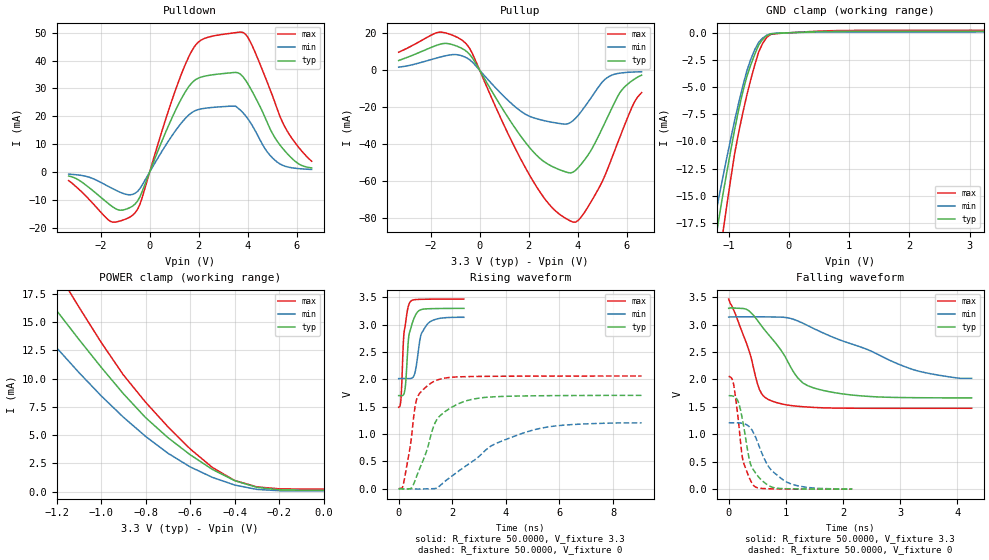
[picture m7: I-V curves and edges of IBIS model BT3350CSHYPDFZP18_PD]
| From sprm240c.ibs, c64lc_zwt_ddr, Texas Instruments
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|   Model Cell BT3350CSHYPDFZP18
[Model]   BT3350CSHYPDFZP18_PD
Model_type   I/O
Polarity   Non-Inverting
Enable   Active-Low
Vinl =  0.8V
Vinh =  2V
Cref =  15.0000pF
Rref =  100.0000M
Vref =  0V
Vmeas =  1.65
C_comp   1.700009p   1.65486p   1.747447p
[Model Spec]
Vinl   0.8V   0.8V   0.8V
Vinh   2V   2V   2V
[Temperature Range]   25   125   -40
[Voltage Range]   3.3   3.14   3.47
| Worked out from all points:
|   slope of the pulldown table from 0 to 0.495 V, typ, clamps not added: 45.1 ohm
|   slope of the pullup table from 0 to 0.495 V, typ, clamps not added: 43.8 ohm
|   GND clamp passes 1 mA (typ) near -0.48 V on its own axis
|   POWER clamp passes 1 mA (typ) near -0.40 V on its own axis
|   rising waveform, R_fixture 50.0000, V_fixture 3.3: 20-80 % time 205ps typ, 283ps min, 156ps max; typ from 1.7 V to 3.29 V
|   rising waveform, R_fixture 50.0000, V_fixture 0: 20-80 % time 856ps typ, 2.32ns min, 382ps max; typ from 0 V to 1.71 V
|   falling waveform, R_fixture 50.0000, V_fixture 3.3: 20-80 % time 667ps typ, 1.54ns min, 357ps max; typ from 3.3 V to 1.66 V
|   falling waveform, R_fixture 50.0000, V_fixture 0: 20-80 % time 215ps typ, 397ps min, 162ps max; typ from 1.7 V to 0.002 V
[POWER_clamp]
|   voltage   I(typ)   I(min)   I(max)
-3.3V     82.99mA    62.31mA    100.8mA
-1.4V     21.51mA    17.33mA    26.18mA
-1.267V   17.8mA     14.25mA    21.77mA
-1.233V   16.92mA    13.5mA     20.67mA
-1.133V   14.33mA    11.28mA    17.43mA
-900mV    8.67mA     6.594mA    10.34mA
-800mV    6.551mA    4.892mA    7.912mA
-600mV    3.27mA     2.197mA    3.79mA
-500mV    1.971mA    1.27mA     2.143mA
-400mV    978.7uA    590.6uA    989.7uA
-300mV    386.3uA    203.8uA    426.6uA
0V        134.3uA    72.54uA    231uA
[Pulldown]
|   voltage   I(typ)   I(min)   I(max)
-3.3V     -1.415mA   -746uA     -3.052mA
-1.6V     -11.86mA   -5.526mA   -17.66mA
-700mV    -12.23mA   -8.018mA   -15.5mA
-400mV    -8.952mA   -5.978mA   -11.65mA
900mV     19.24mA    12.9mA     25.53mA
1.7V      31.81mA    21.22mA    43.17mA
2.2V      34.3mA     22.8mA     47.78mA
3.7V      35.12mA    22.19mA    50.19mA
4.1V      30.16mA    17.85mA    46.75mA
5.1V      12.38mA    4.293mA    25.08mA
5.7V      5.755mA    1.687mA    13.38mA
6.6V      1.491mA    937.8uA    3.885mA
[Pullup]
|   voltage   I(typ)   I(min)   I(max)
-3.3V     5.278mA    1.679mA    9.743mA
-1.7V     13.72mA    6.799mA    20.48mA
-600mV    10.83mA    7.151mA    14.99mA
1.3V      -28.42mA   -18.04mA   -38.22mA
2.2V      -44.3mA    -25.71mA   -60.41mA
3V        -52.29mA   -28.23mA   -74.9mA
3.8V      -55.14mA   -27.3mA    -82.1mA
4.3V      -48.01mA   -19.44mA   -76.31mA
5.2V      -25.74mA   -3.982mA   -53.85mA
5.8V      -10.57mA   -1.415mA   -33.25mA
6.3V      -4.872mA   -941uA     -17.38mA
6.6V      -2.663mA   -794.7uA   -12.11mA
[GND_clamp]
|   voltage   I(typ)   I(min)   I(max)
-3.3V     -102mA     -77.67mA   -122mA
-1.3V     -22.07mA   -19.16mA   -26.6mA
-1.233V   -19.65mA   -17.23mA   -23.92mA
-1.167V   -17.32mA   -15.33mA   -21.26mA
-1.1V     -15.08mA   -13.44mA   -18.61mA
-1.033V   -12.97mA   -11.61mA   -16.04mA
-900mV    -8.917mA   -8.084mA   -11.14mA
-700mV    -4.089mA   -3.566mA   -5.808mA
-500mV    -1.121mA   -869uA     -1.76mA
-366.7mV  -263.4uA   -227.2uA   -428.1uA
633.3mV   109.6uA    61.6uA     173.5uA
3.233V    134.1uA    74.92uA    229.9uA
[Ramp]
| variable   typ   min   max
dV/dt_f  0.9847599/0.6632085n  0.7323867/1.723531n   1.200201/0.358252n
dV/dt_r   1.029494/0.8598868n  0.7430672/2.445214n   1.240708/0.3818052n
R_load = 50
[Rising Waveform]
R_fixture = 50.0000
V_fixture = 3.3
V_fixture_min = 3.14
V_fixture_max = 3.47
|   time   V(typ)   V(min)   V(max)
0s        1.701V     2.012V     1.489V
88ps      1.702V     2.013V     1.658V
176ps     1.715V     2.013V     2.685V
232ps     1.805V     2.013V     2.943V
360ps     2.7V       2.013V     3.334V
416ps     2.873V     2.013V     3.404V
584ps     3.126V     2.081V     3.453V
816ps     3.268V     2.781V     3.459V
1.056ns   3.287V     2.998V     3.462V
2.432ns   3.294V     3.132V     3.465V
[Rising Waveform]
R_fixture = 50.0000
V_fixture = 0
V_fixture_min = 0
V_fixture_max = 0
|   time   V(typ)   V(min)   V(max)
0s        45.61uV    24.35uV    73.91uV
200ps     -6.345mV   30.5uV     139.3mV
472ps     11.97mV    -1.303mV   917.6mV
584ps     117.3mV    -2.375mV   1.407V
672ps     231.3mV    -4.815mV   1.635V
1.36ns    1.206V     4.286mV    1.971V
2.552ns   1.61V      432.2mV    2.048V
3.504ns   1.679V     797.9mV    2.054V
4.72ns    1.696V     1.029V     2.057V
9.064ns   1.706V     1.203V     2.059V
[Falling Waveform]
R_fixture = 50.0000
V_fixture = 3.3
V_fixture_min = 3.14
V_fixture_max = 3.47
|   time   V(typ)   V(min)   V(max)
0s        3.297V     3.138V     3.465V
352ps     3.252V     3.142V     2.539V
536ps     3.031V     3.143V     1.822V
712ps     2.799V     3.14V      1.626V
920ps     2.526V     3.136V     1.557V
1.2ns     2.039V     3.07V      1.512V
1.48ns    1.848V     2.932V     1.491V
2.224ns   1.709V     2.622V     1.476V
3.208ns   1.669V     2.186V     1.475V
4.248ns   1.664V     2.02V      1.475V
[Falling Waveform]
R_fixture = 50.0000
V_fixture = 0
V_fixture_min = 0
V_fixture_max = 0
|   time   V(typ)   V(min)   V(max)
0s        1.704V     1.209V     2.057V
88ps      1.693V     1.21V      1.902V
168ps     1.591V     1.21V      1.268V
248ps     1.231V     1.199V     533mV
368ps     512.3mV    1.131V     192.2mV
456ps     317.2mV    982.1mV    48.57mV
704ps     63.91mV    402.9mV    8.245mV
1.016ns   8.732mV    129.5mV    3.629mV
1.448ns   4.013mV    25.25mV    1.725mV
2.16ns    2.321mV    6.408mV    863.5uV
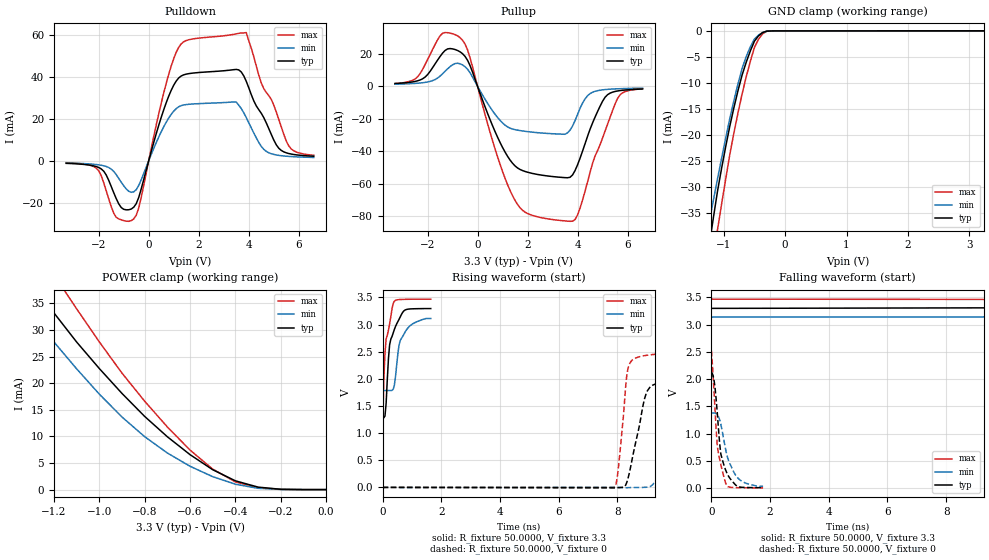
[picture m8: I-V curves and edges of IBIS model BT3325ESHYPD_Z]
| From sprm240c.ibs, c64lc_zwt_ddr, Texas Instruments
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|   Model Cell BT3325ESHYPDFZSCP18
[Model]   BT3325ESHYPD_Z
Model_type   I/O
Polarity   Non-Inverting
Enable   Active-Low
Vinl =  0.8V
Vinh =  2V
Cref =  15.0000pF
Rref =  100.0000M
Vref =  0V
Vmeas =  1.65
C_comp   2.519588p   2.450856p   2.584209p
[Model Spec]
Vinl   0.8V   0.8V   0.8V
Vinh   2V   2V   2V
[Temperature Range]   25   125   -40
[Voltage Range]   3.3   3.14   3.47
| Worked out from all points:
|   slope of the pulldown table from 0 to 0.495 V, typ, clamps not added: 24.1 ohm
|   slope of the pullup table from 0 to 0.495 V, typ, clamps not added: 24.3 ohm
|   GND clamp passes 1 mA (typ) near -0.44 V on its own axis
|   POWER clamp passes 1 mA (typ) near -0.34 V on its own axis
|   rising waveform, R_fixture 50.0000, V_fixture 3.3: 20-80 % time 257ps typ, 308ps min, 205ps max; typ from 1.28 V to 3.29 V
|   rising waveform, R_fixture 50.0000, V_fixture 0: 20-80 % time 495ps typ, 2.09ns min, 249ps max; typ from 0 V to 2.12 V
|   falling waveform, R_fixture 50.0000, V_fixture 3.3: 20-80 % time 3.43ns typ, 13.6ns min, 481ps max; typ from 3.3 V to 1.28 V
|   falling waveform, R_fixture 50.0000, V_fixture 0: 20-80 % time 272ps typ, 409ps min, 228ps max; typ from 2.13 V to 0.005 V
[POWER_clamp]
|   voltage   I(typ)   I(min)   I(max)
-3.3V     190.9mA    141.6mA    233.8mA
-1.367V   44.17mA    36.57mA    51.83mA
-1.267V   37.42mA    31.26mA    44.82mA
-1.233V   35.34mA    29.52mA    42.62mA
-1.133V   29.6mA     24.41mA    36.15mA
-1V       22.79mA    17.97mA    27.8mA
-800mV    13.77mA    9.958mA    16.63mA
-600mV    6.58mA     4.395mA    7.439mA
-500mV    3.742mA    2.435mA    3.858mA
-400mV    1.65mA     1.015mA    1.455mA
-300mV    469.7uA    243.9uA    356.6uA
0V        124.7nA    287.7nA    245.6nA
[Pulldown]
|   voltage   I(typ)   I(min)   I(max)
-3.3V     -1.263mA   -1.107mA   -949.1uA
-2.1V     -2.8mA     -1.831mA   -3.557mA
-1.3V     -18.12mA   -6.64mA    -27.06mA
-600mV    -22.25mA   -14.9mA    -27.84mA
-400mV    -17.58mA   -11.86mA   -22.67mA
700mV     27.76mA    18.41mA    37.04mA
1.2V      39.59mA    25.8mA     54.25mA
3.5V      43.66mA    28.05mA    60.67mA
3.9V      37.99mA    20.64mA    61.29mA
4.6V      20.62mA    5.44mA     34.49mA
5.6V      3.432mA    2.063mA    7.065mA
6.6V      2.132mA    1.558mA    2.581mA
[Pullup]
|   voltage   I(typ)   I(min)   I(max)
-3.3V     1.672mA    1.264mA    1.614mA
-2.4V     3.321mA    1.859mA    5.724mA
-1.4V     20.34mA    7.635mA    32.58mA
-700mV    21.21mA    13.85mA    29.95mA
-400mV    16.02mA    10.48mA    22.44mA
1.5V      -49.06mA   -26.73mA   -70.3mA
3.7V      -56.06mA   -27.03mA   -83.17mA
4V        -48.38mA   -17.36mA   -79.25mA
4.4V      -30.79mA   -5.861mA   -58.89mA
5.1V      -6.795mA   -2.058mA   -27.63mA
5.7V      -2.676mA   -1.512mA   -5.259mA
6.6V      -1.699mA   -1.172mA   -1.592mA
[GND_clamp]
|   voltage   I(typ)   I(min)   I(max)
-3.3V     -223.6mA   -167.5mA   -272.3mA
-1.3V     -46.73mA   -40.78mA   -53.93mA
-1.233V   -41.16mA   -36.62mA   -48.55mA
-1.167V   -35.84mA   -32.5mA    -43.32mA
-1.1V     -30.78mA   -28.42mA   -38.22mA
-1.033V   -26.39mA   -24.46mA   -33.27mA
-900mV    -18.31mA   -16.82mA   -23.74mA
-700mV    -8.481mA   -7.212mA   -12.11mA
-500mV    -1.993mA   -1.59mA    -3.212mA
-366.7mV  -323.4uA   -319.5uA   -566.5uA
-166.7mV  -8.585uA   -10.95uA   -10.74uA
3.233V    68.5nA     4.312uA    202.3nA
[Ramp]
| variable   typ   min   max
dV/dt_f   1.219647/3.400385n   0.8159942/15.49562n   1.486218/0.4594268n
dV/dt_r   1.281407/0.4916932n  0.8226225/1.387687n   1.518912/0.2481368n
R_load = 50
[Rising Waveform]
R_fixture = 50.0000
V_fixture = 3.3
V_fixture_min = 3.14
V_fixture_max = 3.47
|   time   V(typ)   V(min)   V(max)
0s        1.28V      1.783V     1.007V
40ps      1.282V     1.785V     1.969V
80ps      1.315V     1.785V     2.471V
120ps     1.553V     1.785V     2.733V
240ps     2.632V     1.785V     3.022V
360ps     2.844V     1.807V     3.388V
560ps     3.096V     2.622V     3.46V
640ps     3.185V     2.746V     3.462V
1ns       3.29V      3.005V     3.467V
1.64ns    3.295V     3.111V     3.469V
[Rising Waveform]
R_fixture = 50.0000
V_fixture = 0
V_fixture_min = 0
V_fixture_max = 0
|   time   V(typ)   V(min)   V(max)
0s        53.37uV    43.16uV    67.73uV
7.88ns    -8.339mV   108uV      706.2uV
8ns       -5.466mV   33.53uV    204.6mV
8.32ns    91.17mV    -5.729mV   2.066V
8.44ns    348.3mV    -3.154mV   2.302V
9ns       1.763V     3.19mV     2.434V
10.52ns   2.01V      869.2mV    2.482V
18.8ns    2.086V     1.296V     2.506V
26.8ns    2.094V     1.328V     2.51V
202.6ns   2.123V     1.348V     2.522V
[Falling Waveform]
R_fixture = 50.0000
V_fixture = 3.3
V_fixture_min = 3.14
V_fixture_max = 3.47
|   time   V(typ)   V(min)   V(max)
0s        3.3V       3.14V      3.47V
9.8ns     3.31V      3.144V     3.464V
10ns      3.303V     3.144V     3.046V
10.4ns    2.99V      3.144V     1.598V
10.72ns   2.445V     3.14V      1.407V
11.2ns    1.82V      3.026V     1.338V
13.44ns   1.701V     2.206V     1.194V
19.56ns   1.558V     2.122V     1.084V
75.28ns   1.32V      1.904V     1.01V
263.7ns   1.281V     1.808V     1.007V
[Falling Waveform]
R_fixture = 50.0000
V_fixture = 0
V_fixture_min = 0
V_fixture_max = 0
|   time   V(typ)   V(min)   V(max)
0s        2.127V     1.373V     2.522V
80ps      2.015V     1.378V     1.86V
120ps     1.86V      1.374V     1.466V
200ps     1.378V     1.346V     765.5mV
280ps     819.9mV    1.256V     530.1mV
320ps     627mV      1.173V     432mV
480ps     334.7mV    719.6mV    95.96mV
600ps     200.9mV    480mV      16.65mV
920ps     23.09mV    172mV      5.188mV
1.76ns    5.018mV    30.1mV     1.543mV
